VERSION 5.7 ;
  NOWIREEXTENSIONATPIN ON ;
  DIVIDERCHAR "/" ;
  BUSBITCHARS "[]" ;
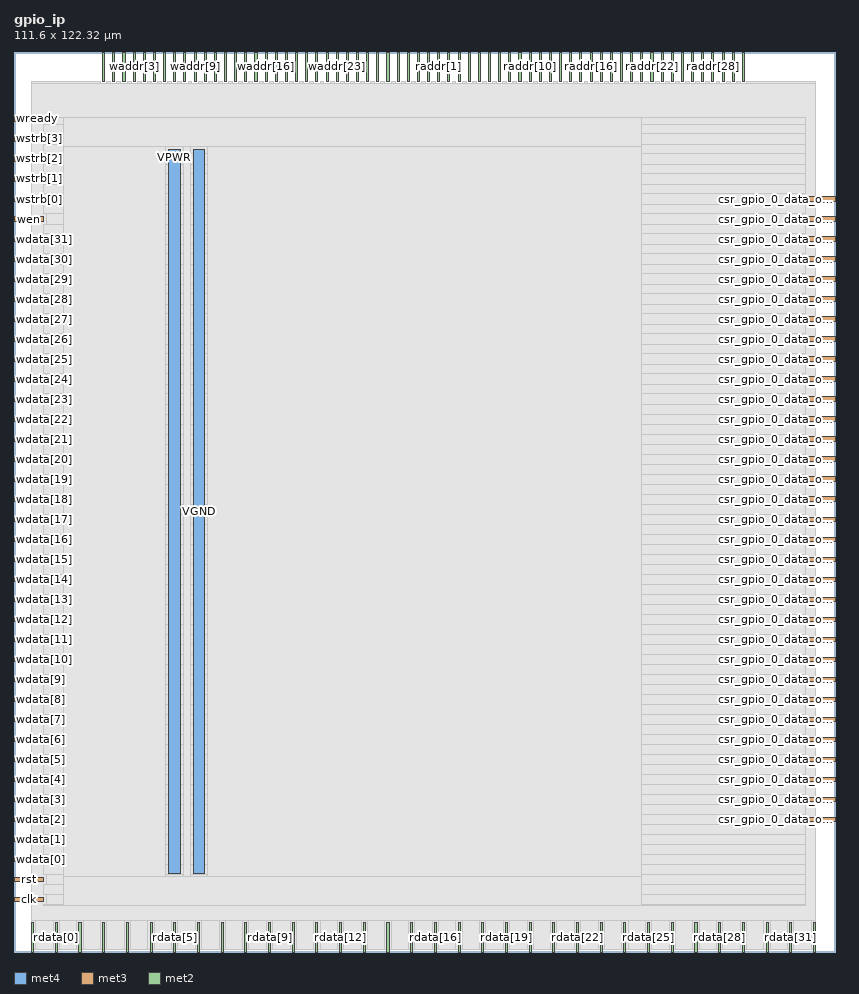
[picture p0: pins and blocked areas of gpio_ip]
MACRO gpio_ip
  CLASS BLOCK ;
  FOREIGN gpio_ip ;
  ORIGIN 0.000 0.000 ;
  SIZE 111.600 BY 122.320 ;
  PIN VGND
    DIRECTION INOUT ;
    USE GROUND ;
    PORT
      LAYER met4 ;
        RECT 24.340 10.640 25.940 109.040 ;
    END
  END VGND
  PIN VPWR
    DIRECTION INOUT ;
    USE POWER ;
    PORT
      LAYER met4 ;
        RECT 21.040 10.640 22.640 109.040 ;
    END
  END VPWR
  PIN clk
    DIRECTION INPUT ;
    USE SIGNAL ;
    ANTENNAGATEAREA 1.286700 ;
    ANTENNADIFFAREA 0.434700 ;
    PORT
      LAYER met3 ;
        RECT 0.000 6.840 4.000 7.440 ;
    END
  END clk
  PIN csr_gpio_0_data_out[0]
    DIRECTION OUTPUT ;
    USE SIGNAL ;
    ANTENNAGATEAREA 0.434700 ;
    ANTENNADIFFAREA 0.880200 ;
    PORT
      LAYER met3 ;
        RECT 107.600 17.720 111.600 18.320 ;
    END
  END csr_gpio_0_data_out[0]
  PIN csr_gpio_0_data_out[10]
    DIRECTION OUTPUT ;
    USE SIGNAL ;
    ANTENNAGATEAREA 0.434700 ;
    ANTENNADIFFAREA 0.880200 ;
    PORT
      LAYER met3 ;
        RECT 107.600 44.920 111.600 45.520 ;
    END
  END csr_gpio_0_data_out[10]
  PIN csr_gpio_0_data_out[11]
    DIRECTION OUTPUT ;
    USE SIGNAL ;
    ANTENNAGATEAREA 0.434700 ;
    ANTENNADIFFAREA 0.880200 ;
    PORT
      LAYER met3 ;
        RECT 107.600 47.640 111.600 48.240 ;
    END
  END csr_gpio_0_data_out[11]
  PIN csr_gpio_0_data_out[12]
    DIRECTION OUTPUT ;
    USE SIGNAL ;
    ANTENNAGATEAREA 0.434700 ;
    ANTENNADIFFAREA 0.880200 ;
    PORT
      LAYER met3 ;
        RECT 107.600 50.360 111.600 50.960 ;
    END
  END csr_gpio_0_data_out[12]
  PIN csr_gpio_0_data_out[13]
    DIRECTION OUTPUT ;
    USE SIGNAL ;
    ANTENNAGATEAREA 0.434700 ;
    ANTENNADIFFAREA 0.880200 ;
    PORT
      LAYER met3 ;
        RECT 107.600 53.080 111.600 53.680 ;
    END
  END csr_gpio_0_data_out[13]
  PIN csr_gpio_0_data_out[14]
    DIRECTION OUTPUT ;
    USE SIGNAL ;
    ANTENNAGATEAREA 0.434700 ;
    ANTENNADIFFAREA 0.880200 ;
    PORT
      LAYER met3 ;
        RECT 107.600 55.800 111.600 56.400 ;
    END
  END csr_gpio_0_data_out[14]
  PIN csr_gpio_0_data_out[15]
    DIRECTION OUTPUT ;
    USE SIGNAL ;
    ANTENNAGATEAREA 0.434700 ;
    ANTENNADIFFAREA 0.880200 ;
    PORT
      LAYER met3 ;
        RECT 107.600 58.520 111.600 59.120 ;
    END
  END csr_gpio_0_data_out[15]
  PIN csr_gpio_0_data_out[16]
    DIRECTION OUTPUT ;
    USE SIGNAL ;
    ANTENNAGATEAREA 0.434700 ;
    ANTENNADIFFAREA 0.880200 ;
    PORT
      LAYER met3 ;
        RECT 107.600 61.240 111.600 61.840 ;
    END
  END csr_gpio_0_data_out[16]
  PIN csr_gpio_0_data_out[17]
    DIRECTION OUTPUT ;
    USE SIGNAL ;
    ANTENNAGATEAREA 0.434700 ;
    ANTENNADIFFAREA 0.880200 ;
    PORT
      LAYER met3 ;
        RECT 107.600 63.960 111.600 64.560 ;
    END
  END csr_gpio_0_data_out[17]
  PIN csr_gpio_0_data_out[18]
    DIRECTION OUTPUT ;
    USE SIGNAL ;
    ANTENNAGATEAREA 0.434700 ;
    ANTENNADIFFAREA 0.880200 ;
    PORT
      LAYER met3 ;
        RECT 107.600 66.680 111.600 67.280 ;
    END
  END csr_gpio_0_data_out[18]
  PIN csr_gpio_0_data_out[19]
    DIRECTION OUTPUT ;
    USE SIGNAL ;
    ANTENNAGATEAREA 0.434700 ;
    ANTENNADIFFAREA 0.880200 ;
    PORT
      LAYER met3 ;
        RECT 107.600 69.400 111.600 70.000 ;
    END
  END csr_gpio_0_data_out[19]
  PIN csr_gpio_0_data_out[1]
    DIRECTION OUTPUT ;
    USE SIGNAL ;
    ANTENNAGATEAREA 0.434700 ;
    ANTENNADIFFAREA 0.880200 ;
    PORT
      LAYER met3 ;
        RECT 107.600 20.440 111.600 21.040 ;
    END
  END csr_gpio_0_data_out[1]
  PIN csr_gpio_0_data_out[20]
    DIRECTION OUTPUT ;
    USE SIGNAL ;
    ANTENNAGATEAREA 0.434700 ;
    ANTENNADIFFAREA 0.880200 ;
    PORT
      LAYER met3 ;
        RECT 107.600 72.120 111.600 72.720 ;
    END
  END csr_gpio_0_data_out[20]
  PIN csr_gpio_0_data_out[21]
    DIRECTION OUTPUT ;
    USE SIGNAL ;
    ANTENNAGATEAREA 0.434700 ;
    ANTENNADIFFAREA 0.880200 ;
    PORT
      LAYER met3 ;
        RECT 107.600 74.840 111.600 75.440 ;
    END
  END csr_gpio_0_data_out[21]
  PIN csr_gpio_0_data_out[22]
    DIRECTION OUTPUT ;
    USE SIGNAL ;
    ANTENNAGATEAREA 0.434700 ;
    ANTENNADIFFAREA 0.880200 ;
    PORT
      LAYER met3 ;
        RECT 107.600 77.560 111.600 78.160 ;
    END
  END csr_gpio_0_data_out[22]
  PIN csr_gpio_0_data_out[23]
    DIRECTION OUTPUT ;
    USE SIGNAL ;
    ANTENNAGATEAREA 0.434700 ;
    ANTENNADIFFAREA 0.880200 ;
    PORT
      LAYER met3 ;
        RECT 107.600 80.280 111.600 80.880 ;
    END
  END csr_gpio_0_data_out[23]
  PIN csr_gpio_0_data_out[24]
    DIRECTION OUTPUT ;
    USE SIGNAL ;
    ANTENNAGATEAREA 0.434700 ;
    ANTENNADIFFAREA 0.880200 ;
    PORT
      LAYER met3 ;
        RECT 107.600 83.000 111.600 83.600 ;
    END
  END csr_gpio_0_data_out[24]
  PIN csr_gpio_0_data_out[25]
    DIRECTION OUTPUT ;
    USE SIGNAL ;
    ANTENNAGATEAREA 0.434700 ;
    ANTENNADIFFAREA 0.880200 ;
    PORT
      LAYER met3 ;
        RECT 107.600 85.720 111.600 86.320 ;
    END
  END csr_gpio_0_data_out[25]
  PIN csr_gpio_0_data_out[26]
    DIRECTION OUTPUT ;
    USE SIGNAL ;
    ANTENNAGATEAREA 0.434700 ;
    ANTENNADIFFAREA 0.880200 ;
    PORT
      LAYER met3 ;
        RECT 107.600 88.440 111.600 89.040 ;
    END
  END csr_gpio_0_data_out[26]
  PIN csr_gpio_0_data_out[27]
    DIRECTION OUTPUT ;
    USE SIGNAL ;
    ANTENNAGATEAREA 0.434700 ;
    ANTENNADIFFAREA 0.880200 ;
    PORT
      LAYER met3 ;
        RECT 107.600 91.160 111.600 91.760 ;
    END
  END csr_gpio_0_data_out[27]
  PIN csr_gpio_0_data_out[28]
    DIRECTION OUTPUT ;
    USE SIGNAL ;
    ANTENNAGATEAREA 0.434700 ;
    ANTENNADIFFAREA 0.880200 ;
    PORT
      LAYER met3 ;
        RECT 107.600 93.880 111.600 94.480 ;
    END
  END csr_gpio_0_data_out[28]
  PIN csr_gpio_0_data_out[29]
    DIRECTION OUTPUT ;
    USE SIGNAL ;
    ANTENNAGATEAREA 0.434700 ;
    ANTENNADIFFAREA 0.880200 ;
    PORT
      LAYER met3 ;
        RECT 107.600 96.600 111.600 97.200 ;
    END
  END csr_gpio_0_data_out[29]
  PIN csr_gpio_0_data_out[2]
    DIRECTION OUTPUT ;
    USE SIGNAL ;
    ANTENNAGATEAREA 0.434700 ;
    ANTENNADIFFAREA 0.880200 ;
    PORT
      LAYER met3 ;
        RECT 107.600 23.160 111.600 23.760 ;
    END
  END csr_gpio_0_data_out[2]
  PIN csr_gpio_0_data_out[30]
    DIRECTION OUTPUT ;
    USE SIGNAL ;
    ANTENNAGATEAREA 0.434700 ;
    ANTENNADIFFAREA 0.880200 ;
    PORT
      LAYER met3 ;
        RECT 107.600 99.320 111.600 99.920 ;
    END
  END csr_gpio_0_data_out[30]
  PIN csr_gpio_0_data_out[31]
    DIRECTION OUTPUT ;
    USE SIGNAL ;
    ANTENNAGATEAREA 0.434700 ;
    ANTENNADIFFAREA 0.880200 ;
    PORT
      LAYER met3 ;
        RECT 107.600 102.040 111.600 102.640 ;
    END
  END csr_gpio_0_data_out[31]
  PIN csr_gpio_0_data_out[3]
    DIRECTION OUTPUT ;
    USE SIGNAL ;
    ANTENNAGATEAREA 0.434700 ;
    ANTENNADIFFAREA 0.880200 ;
    PORT
      LAYER met3 ;
        RECT 107.600 25.880 111.600 26.480 ;
    END
  END csr_gpio_0_data_out[3]
  PIN csr_gpio_0_data_out[4]
    DIRECTION OUTPUT ;
    USE SIGNAL ;
    ANTENNAGATEAREA 0.434700 ;
    ANTENNADIFFAREA 0.880200 ;
    PORT
      LAYER met3 ;
        RECT 107.600 28.600 111.600 29.200 ;
    END
  END csr_gpio_0_data_out[4]
  PIN csr_gpio_0_data_out[5]
    DIRECTION OUTPUT ;
    USE SIGNAL ;
    ANTENNAGATEAREA 0.434700 ;
    ANTENNADIFFAREA 0.880200 ;
    PORT
      LAYER met3 ;
        RECT 107.600 31.320 111.600 31.920 ;
    END
  END csr_gpio_0_data_out[5]
  PIN csr_gpio_0_data_out[6]
    DIRECTION OUTPUT ;
    USE SIGNAL ;
    ANTENNAGATEAREA 0.434700 ;
    ANTENNADIFFAREA 0.880200 ;
    PORT
      LAYER met3 ;
        RECT 107.600 34.040 111.600 34.640 ;
    END
  END csr_gpio_0_data_out[6]
  PIN csr_gpio_0_data_out[7]
    DIRECTION OUTPUT ;
    USE SIGNAL ;
    ANTENNAGATEAREA 0.434700 ;
    ANTENNADIFFAREA 0.880200 ;
    PORT
      LAYER met3 ;
        RECT 107.600 36.760 111.600 37.360 ;
    END
  END csr_gpio_0_data_out[7]
  PIN csr_gpio_0_data_out[8]
    DIRECTION OUTPUT ;
    USE SIGNAL ;
    ANTENNAGATEAREA 0.434700 ;
    ANTENNADIFFAREA 0.880200 ;
    PORT
      LAYER met3 ;
        RECT 107.600 39.480 111.600 40.080 ;
    END
  END csr_gpio_0_data_out[8]
  PIN csr_gpio_0_data_out[9]
    DIRECTION OUTPUT ;
    USE SIGNAL ;
    ANTENNAGATEAREA 0.434700 ;
    ANTENNADIFFAREA 0.880200 ;
    PORT
      LAYER met3 ;
        RECT 107.600 42.200 111.600 42.800 ;
    END
  END csr_gpio_0_data_out[9]
  PIN raddr[0]
    DIRECTION INPUT ;
    USE SIGNAL ;
    ANTENNAGATEAREA 0.631200 ;
    ANTENNADIFFAREA 0.434700 ;
    PORT
      LAYER met2 ;
        RECT 56.210 118.320 56.490 122.320 ;
    END
  END raddr[0]
  PIN raddr[10]
    DIRECTION INPUT ;
    USE SIGNAL ;
    ANTENNAGATEAREA 0.631200 ;
    ANTENNADIFFAREA 0.434700 ;
    PORT
      LAYER met2 ;
        RECT 70.010 118.320 70.290 122.320 ;
    END
  END raddr[10]
  PIN raddr[11]
    DIRECTION INPUT ;
    USE SIGNAL ;
    ANTENNAGATEAREA 0.631200 ;
    ANTENNADIFFAREA 0.434700 ;
    PORT
      LAYER met2 ;
        RECT 71.390 118.320 71.670 122.320 ;
    END
  END raddr[11]
  PIN raddr[12]
    DIRECTION INPUT ;
    USE SIGNAL ;
    ANTENNAGATEAREA 0.631200 ;
    ANTENNADIFFAREA 0.434700 ;
    PORT
      LAYER met2 ;
        RECT 72.770 118.320 73.050 122.320 ;
    END
  END raddr[12]
  PIN raddr[13]
    DIRECTION INPUT ;
    USE SIGNAL ;
    ANTENNAGATEAREA 0.631200 ;
    ANTENNADIFFAREA 0.434700 ;
    PORT
      LAYER met2 ;
        RECT 74.150 118.320 74.430 122.320 ;
    END
  END raddr[13]
  PIN raddr[14]
    DIRECTION INPUT ;
    USE SIGNAL ;
    ANTENNAGATEAREA 0.631200 ;
    ANTENNADIFFAREA 0.434700 ;
    PORT
      LAYER met2 ;
        RECT 75.530 118.320 75.810 122.320 ;
    END
  END raddr[14]
  PIN raddr[15]
    DIRECTION INPUT ;
    USE SIGNAL ;
    ANTENNAGATEAREA 0.631200 ;
    ANTENNADIFFAREA 0.434700 ;
    PORT
      LAYER met2 ;
        RECT 76.910 118.320 77.190 122.320 ;
    END
  END raddr[15]
  PIN raddr[16]
    DIRECTION INPUT ;
    USE SIGNAL ;
    ANTENNAGATEAREA 0.631200 ;
    ANTENNADIFFAREA 0.434700 ;
    PORT
      LAYER met2 ;
        RECT 78.290 118.320 78.570 122.320 ;
    END
  END raddr[16]
  PIN raddr[17]
    DIRECTION INPUT ;
    USE SIGNAL ;
    ANTENNAGATEAREA 0.631200 ;
    ANTENNADIFFAREA 0.434700 ;
    PORT
      LAYER met2 ;
        RECT 79.670 118.320 79.950 122.320 ;
    END
  END raddr[17]
  PIN raddr[18]
    DIRECTION INPUT ;
    USE SIGNAL ;
    ANTENNAGATEAREA 0.631200 ;
    ANTENNADIFFAREA 0.434700 ;
    PORT
      LAYER met2 ;
        RECT 81.050 118.320 81.330 122.320 ;
    END
  END raddr[18]
  PIN raddr[19]
    DIRECTION INPUT ;
    USE SIGNAL ;
    ANTENNAGATEAREA 0.631200 ;
    ANTENNADIFFAREA 0.434700 ;
    PORT
      LAYER met2 ;
        RECT 82.430 118.320 82.710 122.320 ;
    END
  END raddr[19]
  PIN raddr[1]
    DIRECTION INPUT ;
    USE SIGNAL ;
    ANTENNAGATEAREA 0.631200 ;
    ANTENNADIFFAREA 0.434700 ;
    PORT
      LAYER met2 ;
        RECT 57.590 118.320 57.870 122.320 ;
    END
  END raddr[1]
  PIN raddr[20]
    DIRECTION INPUT ;
    USE SIGNAL ;
    ANTENNAGATEAREA 0.631200 ;
    ANTENNADIFFAREA 0.434700 ;
    PORT
      LAYER met2 ;
        RECT 83.810 118.320 84.090 122.320 ;
    END
  END raddr[20]
  PIN raddr[21]
    DIRECTION INPUT ;
    USE SIGNAL ;
    ANTENNAGATEAREA 0.631200 ;
    ANTENNADIFFAREA 0.434700 ;
    PORT
      LAYER met2 ;
        RECT 85.190 118.320 85.470 122.320 ;
    END
  END raddr[21]
  PIN raddr[22]
    DIRECTION INPUT ;
    USE SIGNAL ;
    ANTENNAGATEAREA 0.631200 ;
    ANTENNADIFFAREA 0.434700 ;
    PORT
      LAYER met2 ;
        RECT 86.570 118.320 86.850 122.320 ;
    END
  END raddr[22]
  PIN raddr[23]
    DIRECTION INPUT ;
    USE SIGNAL ;
    ANTENNAGATEAREA 0.631200 ;
    ANTENNADIFFAREA 0.434700 ;
    PORT
      LAYER met2 ;
        RECT 87.950 118.320 88.230 122.320 ;
    END
  END raddr[23]
  PIN raddr[24]
    DIRECTION INPUT ;
    USE SIGNAL ;
    ANTENNAGATEAREA 0.631200 ;
    ANTENNADIFFAREA 0.434700 ;
    PORT
      LAYER met2 ;
        RECT 89.330 118.320 89.610 122.320 ;
    END
  END raddr[24]
  PIN raddr[25]
    DIRECTION INPUT ;
    USE SIGNAL ;
    ANTENNAGATEAREA 0.560700 ;
    ANTENNADIFFAREA 0.434700 ;
    PORT
      LAYER met2 ;
        RECT 90.710 118.320 90.990 122.320 ;
    END
  END raddr[25]
  PIN raddr[26]
    DIRECTION INPUT ;
    USE SIGNAL ;
    ANTENNAGATEAREA 0.631200 ;
    ANTENNADIFFAREA 0.434700 ;
    PORT
      LAYER met2 ;
        RECT 92.090 118.320 92.370 122.320 ;
    END
  END raddr[26]
  PIN raddr[27]
    DIRECTION INPUT ;
    USE SIGNAL ;
    ANTENNAGATEAREA 0.631200 ;
    ANTENNADIFFAREA 0.434700 ;
    PORT
      LAYER met2 ;
        RECT 93.470 118.320 93.750 122.320 ;
    END
  END raddr[27]
  PIN raddr[28]
    DIRECTION INPUT ;
    USE SIGNAL ;
    ANTENNAGATEAREA 0.631200 ;
    ANTENNADIFFAREA 0.434700 ;
    PORT
      LAYER met2 ;
        RECT 94.850 118.320 95.130 122.320 ;
    END
  END raddr[28]
  PIN raddr[29]
    DIRECTION INPUT ;
    USE SIGNAL ;
    ANTENNAGATEAREA 0.631200 ;
    ANTENNADIFFAREA 0.434700 ;
    PORT
      LAYER met2 ;
        RECT 96.230 118.320 96.510 122.320 ;
    END
  END raddr[29]
  PIN raddr[2]
    DIRECTION INPUT ;
    USE SIGNAL ;
    ANTENNAGATEAREA 0.631200 ;
    ANTENNADIFFAREA 0.434700 ;
    PORT
      LAYER met2 ;
        RECT 58.970 118.320 59.250 122.320 ;
    END
  END raddr[2]
  PIN raddr[30]
    DIRECTION INPUT ;
    USE SIGNAL ;
    ANTENNAGATEAREA 0.631200 ;
    ANTENNADIFFAREA 0.434700 ;
    PORT
      LAYER met2 ;
        RECT 97.610 118.320 97.890 122.320 ;
    END
  END raddr[30]
  PIN raddr[31]
    DIRECTION INPUT ;
    USE SIGNAL ;
    ANTENNAGATEAREA 0.631200 ;
    ANTENNADIFFAREA 0.434700 ;
    PORT
      LAYER met2 ;
        RECT 98.990 118.320 99.270 122.320 ;
    END
  END raddr[31]
  PIN raddr[3]
    DIRECTION INPUT ;
    USE SIGNAL ;
    ANTENNAGATEAREA 0.631200 ;
    ANTENNADIFFAREA 0.434700 ;
    PORT
      LAYER met2 ;
        RECT 60.350 118.320 60.630 122.320 ;
    END
  END raddr[3]
  PIN raddr[4]
    DIRECTION INPUT ;
    USE SIGNAL ;
    ANTENNAGATEAREA 0.631200 ;
    ANTENNADIFFAREA 0.434700 ;
    PORT
      LAYER met2 ;
        RECT 61.730 118.320 62.010 122.320 ;
    END
  END raddr[4]
  PIN raddr[5]
    DIRECTION INPUT ;
    USE SIGNAL ;
    ANTENNAGATEAREA 0.631200 ;
    ANTENNADIFFAREA 0.434700 ;
    PORT
      LAYER met2 ;
        RECT 63.110 118.320 63.390 122.320 ;
    END
  END raddr[5]
  PIN raddr[6]
    DIRECTION INPUT ;
    USE SIGNAL ;
    ANTENNAGATEAREA 0.631200 ;
    ANTENNADIFFAREA 0.434700 ;
    PORT
      LAYER met2 ;
        RECT 64.490 118.320 64.770 122.320 ;
    END
  END raddr[6]
  PIN raddr[7]
    DIRECTION INPUT ;
    USE SIGNAL ;
    ANTENNAGATEAREA 0.631200 ;
    ANTENNADIFFAREA 0.434700 ;
    PORT
      LAYER met2 ;
        RECT 65.870 118.320 66.150 122.320 ;
    END
  END raddr[7]
  PIN raddr[8]
    DIRECTION INPUT ;
    USE SIGNAL ;
    ANTENNAGATEAREA 0.631200 ;
    ANTENNADIFFAREA 0.434700 ;
    PORT
      LAYER met2 ;
        RECT 67.250 118.320 67.530 122.320 ;
    END
  END raddr[8]
  PIN raddr[9]
    DIRECTION INPUT ;
    USE SIGNAL ;
    ANTENNAGATEAREA 0.560700 ;
    ANTENNADIFFAREA 0.434700 ;
    PORT
      LAYER met2 ;
        RECT 68.630 118.320 68.910 122.320 ;
    END
  END raddr[9]
  PIN rdata[0]
    DIRECTION OUTPUT ;
    USE SIGNAL ;
    ANTENNAGATEAREA 0.434700 ;
    ANTENNADIFFAREA 0.880200 ;
    PORT
      LAYER met2 ;
        RECT 5.610 0.000 5.890 4.000 ;
    END
  END rdata[0]
  PIN rdata[10]
    DIRECTION OUTPUT ;
    USE SIGNAL ;
    ANTENNAGATEAREA 0.434700 ;
    ANTENNADIFFAREA 0.880200 ;
    PORT
      LAYER met2 ;
        RECT 37.810 0.000 38.090 4.000 ;
    END
  END rdata[10]
  PIN rdata[11]
    DIRECTION OUTPUT ;
    USE SIGNAL ;
    ANTENNAGATEAREA 0.434700 ;
    ANTENNADIFFAREA 0.880200 ;
    PORT
      LAYER met2 ;
        RECT 41.030 0.000 41.310 4.000 ;
    END
  END rdata[11]
  PIN rdata[12]
    DIRECTION OUTPUT ;
    USE SIGNAL ;
    ANTENNAGATEAREA 0.434700 ;
    ANTENNADIFFAREA 0.880200 ;
    PORT
      LAYER met2 ;
        RECT 44.250 0.000 44.530 4.000 ;
    END
  END rdata[12]
  PIN rdata[13]
    DIRECTION OUTPUT ;
    USE SIGNAL ;
    ANTENNAGATEAREA 0.434700 ;
    ANTENNADIFFAREA 0.880200 ;
    PORT
      LAYER met2 ;
        RECT 47.470 0.000 47.750 4.000 ;
    END
  END rdata[13]
  PIN rdata[14]
    DIRECTION OUTPUT ;
    USE SIGNAL ;
    ANTENNAGATEAREA 0.434700 ;
    ANTENNADIFFAREA 0.880200 ;
    PORT
      LAYER met2 ;
        RECT 50.690 0.000 50.970 4.000 ;
    END
  END rdata[14]
  PIN rdata[15]
    DIRECTION OUTPUT ;
    USE SIGNAL ;
    ANTENNAGATEAREA 0.434700 ;
    ANTENNADIFFAREA 0.880200 ;
    PORT
      LAYER met2 ;
        RECT 53.910 0.000 54.190 4.000 ;
    END
  END rdata[15]
  PIN rdata[16]
    DIRECTION OUTPUT ;
    USE SIGNAL ;
    ANTENNAGATEAREA 0.434700 ;
    ANTENNADIFFAREA 0.880200 ;
    PORT
      LAYER met2 ;
        RECT 57.130 0.000 57.410 4.000 ;
    END
  END rdata[16]
  PIN rdata[17]
    DIRECTION OUTPUT ;
    USE SIGNAL ;
    ANTENNAGATEAREA 0.434700 ;
    ANTENNADIFFAREA 0.880200 ;
    PORT
      LAYER met2 ;
        RECT 60.350 0.000 60.630 4.000 ;
    END
  END rdata[17]
  PIN rdata[18]
    DIRECTION OUTPUT ;
    USE SIGNAL ;
    ANTENNAGATEAREA 0.434700 ;
    ANTENNADIFFAREA 0.880200 ;
    PORT
      LAYER met2 ;
        RECT 63.570 0.000 63.850 4.000 ;
    END
  END rdata[18]
  PIN rdata[19]
    DIRECTION OUTPUT ;
    USE SIGNAL ;
    ANTENNAGATEAREA 0.434700 ;
    ANTENNADIFFAREA 0.880200 ;
    PORT
      LAYER met2 ;
        RECT 66.790 0.000 67.070 4.000 ;
    END
  END rdata[19]
  PIN rdata[1]
    DIRECTION OUTPUT ;
    USE SIGNAL ;
    ANTENNAGATEAREA 0.434700 ;
    ANTENNADIFFAREA 0.880200 ;
    PORT
      LAYER met2 ;
        RECT 8.830 0.000 9.110 4.000 ;
    END
  END rdata[1]
  PIN rdata[20]
    DIRECTION OUTPUT ;
    USE SIGNAL ;
    ANTENNAGATEAREA 0.434700 ;
    ANTENNADIFFAREA 0.880200 ;
    PORT
      LAYER met2 ;
        RECT 70.010 0.000 70.290 4.000 ;
    END
  END rdata[20]
  PIN rdata[21]
    DIRECTION OUTPUT ;
    USE SIGNAL ;
    ANTENNAGATEAREA 0.434700 ;
    ANTENNADIFFAREA 0.880200 ;
    PORT
      LAYER met2 ;
        RECT 73.230 0.000 73.510 4.000 ;
    END
  END rdata[21]
  PIN rdata[22]
    DIRECTION OUTPUT ;
    USE SIGNAL ;
    ANTENNAGATEAREA 0.434700 ;
    ANTENNADIFFAREA 0.880200 ;
    PORT
      LAYER met2 ;
        RECT 76.450 0.000 76.730 4.000 ;
    END
  END rdata[22]
  PIN rdata[23]
    DIRECTION OUTPUT ;
    USE SIGNAL ;
    ANTENNAGATEAREA 0.434700 ;
    ANTENNADIFFAREA 0.880200 ;
    PORT
      LAYER met2 ;
        RECT 79.670 0.000 79.950 4.000 ;
    END
  END rdata[23]
  PIN rdata[24]
    DIRECTION OUTPUT ;
    USE SIGNAL ;
    ANTENNAGATEAREA 0.434700 ;
    ANTENNADIFFAREA 0.880200 ;
    PORT
      LAYER met2 ;
        RECT 82.890 0.000 83.170 4.000 ;
    END
  END rdata[24]
  PIN rdata[25]
    DIRECTION OUTPUT ;
    USE SIGNAL ;
    ANTENNAGATEAREA 0.434700 ;
    ANTENNADIFFAREA 0.880200 ;
    PORT
      LAYER met2 ;
        RECT 86.110 0.000 86.390 4.000 ;
    END
  END rdata[25]
  PIN rdata[26]
    DIRECTION OUTPUT ;
    USE SIGNAL ;
    ANTENNAGATEAREA 0.434700 ;
    ANTENNADIFFAREA 0.880200 ;
    PORT
      LAYER met2 ;
        RECT 89.330 0.000 89.610 4.000 ;
    END
  END rdata[26]
  PIN rdata[27]
    DIRECTION OUTPUT ;
    USE SIGNAL ;
    ANTENNAGATEAREA 0.434700 ;
    ANTENNADIFFAREA 0.880200 ;
    PORT
      LAYER met2 ;
        RECT 92.550 0.000 92.830 4.000 ;
    END
  END rdata[27]
  PIN rdata[28]
    DIRECTION OUTPUT ;
    USE SIGNAL ;
    ANTENNAGATEAREA 0.434700 ;
    ANTENNADIFFAREA 0.880200 ;
    PORT
      LAYER met2 ;
        RECT 95.770 0.000 96.050 4.000 ;
    END
  END rdata[28]
  PIN rdata[29]
    DIRECTION OUTPUT ;
    USE SIGNAL ;
    ANTENNAGATEAREA 0.434700 ;
    ANTENNADIFFAREA 0.880200 ;
    PORT
      LAYER met2 ;
        RECT 98.990 0.000 99.270 4.000 ;
    END
  END rdata[29]
  PIN rdata[2]
    DIRECTION OUTPUT ;
    USE SIGNAL ;
    ANTENNAGATEAREA 0.434700 ;
    ANTENNADIFFAREA 0.880200 ;
    PORT
      LAYER met2 ;
        RECT 12.050 0.000 12.330 4.000 ;
    END
  END rdata[2]
  PIN rdata[30]
    DIRECTION OUTPUT ;
    USE SIGNAL ;
    ANTENNAGATEAREA 0.434700 ;
    ANTENNADIFFAREA 0.880200 ;
    PORT
      LAYER met2 ;
        RECT 102.210 0.000 102.490 4.000 ;
    END
  END rdata[30]
  PIN rdata[31]
    DIRECTION OUTPUT ;
    USE SIGNAL ;
    ANTENNAGATEAREA 0.434700 ;
    ANTENNADIFFAREA 0.880200 ;
    PORT
      LAYER met2 ;
        RECT 105.430 0.000 105.710 4.000 ;
    END
  END rdata[31]
  PIN rdata[3]
    DIRECTION OUTPUT ;
    USE SIGNAL ;
    ANTENNAGATEAREA 0.434700 ;
    ANTENNADIFFAREA 0.880200 ;
    PORT
      LAYER met2 ;
        RECT 15.270 0.000 15.550 4.000 ;
    END
  END rdata[3]
  PIN rdata[4]
    DIRECTION OUTPUT ;
    USE SIGNAL ;
    ANTENNAGATEAREA 0.434700 ;
    ANTENNADIFFAREA 0.880200 ;
    PORT
      LAYER met2 ;
        RECT 18.490 0.000 18.770 4.000 ;
    END
  END rdata[4]
  PIN rdata[5]
    DIRECTION OUTPUT ;
    USE SIGNAL ;
    ANTENNAGATEAREA 0.434700 ;
    ANTENNADIFFAREA 0.880200 ;
    PORT
      LAYER met2 ;
        RECT 21.710 0.000 21.990 4.000 ;
    END
  END rdata[5]
  PIN rdata[6]
    DIRECTION OUTPUT ;
    USE SIGNAL ;
    ANTENNAGATEAREA 0.434700 ;
    ANTENNADIFFAREA 0.880200 ;
    PORT
      LAYER met2 ;
        RECT 24.930 0.000 25.210 4.000 ;
    END
  END rdata[6]
  PIN rdata[7]
    DIRECTION OUTPUT ;
    USE SIGNAL ;
    ANTENNAGATEAREA 0.434700 ;
    ANTENNADIFFAREA 0.880200 ;
    PORT
      LAYER met2 ;
        RECT 28.150 0.000 28.430 4.000 ;
    END
  END rdata[7]
  PIN rdata[8]
    DIRECTION OUTPUT ;
    USE SIGNAL ;
    ANTENNAGATEAREA 0.434700 ;
    ANTENNADIFFAREA 0.880200 ;
    PORT
      LAYER met2 ;
        RECT 31.370 0.000 31.650 4.000 ;
    END
  END rdata[8]
  PIN rdata[9]
    DIRECTION OUTPUT ;
    USE SIGNAL ;
    ANTENNAGATEAREA 0.434700 ;
    ANTENNADIFFAREA 0.880200 ;
    PORT
      LAYER met2 ;
        RECT 34.590 0.000 34.870 4.000 ;
    END
  END rdata[9]
  PIN ren
    DIRECTION INPUT ;
    USE SIGNAL ;
    ANTENNAGATEAREA 0.560700 ;
    ANTENNADIFFAREA 0.434700 ;
    PORT
      LAYER met2 ;
        RECT 2.390 0.000 2.670 4.000 ;
    END
  END ren
  PIN rst
    DIRECTION INPUT ;
    USE SIGNAL ;
    ANTENNAGATEAREA 0.560700 ;
    ANTENNADIFFAREA 0.434700 ;
    PORT
      LAYER met3 ;
        RECT 0.000 9.560 4.000 10.160 ;
    END
  END rst
  PIN rvalid
    DIRECTION OUTPUT ;
    USE SIGNAL ;
    ANTENNAGATEAREA 0.434700 ;
    ANTENNADIFFAREA 0.880200 ;
    PORT
      LAYER met2 ;
        RECT 108.650 0.000 108.930 4.000 ;
    END
  END rvalid
  PIN waddr[0]
    DIRECTION INPUT ;
    USE SIGNAL ;
    ANTENNAGATEAREA 0.631200 ;
    ANTENNADIFFAREA 0.434700 ;
    PORT
      LAYER met2 ;
        RECT 12.050 118.320 12.330 122.320 ;
    END
  END waddr[0]
  PIN waddr[10]
    DIRECTION INPUT ;
    USE SIGNAL ;
    ANTENNAGATEAREA 0.631200 ;
    ANTENNADIFFAREA 0.434700 ;
    PORT
      LAYER met2 ;
        RECT 25.850 118.320 26.130 122.320 ;
    END
  END waddr[10]
  PIN waddr[11]
    DIRECTION INPUT ;
    USE SIGNAL ;
    ANTENNAGATEAREA 0.631200 ;
    ANTENNADIFFAREA 0.434700 ;
    PORT
      LAYER met2 ;
        RECT 27.230 118.320 27.510 122.320 ;
    END
  END waddr[11]
  PIN waddr[12]
    DIRECTION INPUT ;
    USE SIGNAL ;
    ANTENNAGATEAREA 0.631200 ;
    ANTENNADIFFAREA 0.434700 ;
    PORT
      LAYER met2 ;
        RECT 28.610 118.320 28.890 122.320 ;
    END
  END waddr[12]
  PIN waddr[13]
    DIRECTION INPUT ;
    USE SIGNAL ;
    ANTENNAGATEAREA 0.631200 ;
    ANTENNADIFFAREA 0.434700 ;
    PORT
      LAYER met2 ;
        RECT 29.990 118.320 30.270 122.320 ;
    END
  END waddr[13]
  PIN waddr[14]
    DIRECTION INPUT ;
    USE SIGNAL ;
    ANTENNAGATEAREA 0.631200 ;
    ANTENNADIFFAREA 0.434700 ;
    PORT
      LAYER met2 ;
        RECT 31.370 118.320 31.650 122.320 ;
    END
  END waddr[14]
  PIN waddr[15]
    DIRECTION INPUT ;
    USE SIGNAL ;
    ANTENNAGATEAREA 0.631200 ;
    ANTENNADIFFAREA 0.434700 ;
    PORT
      LAYER met2 ;
        RECT 32.750 118.320 33.030 122.320 ;
    END
  END waddr[15]
  PIN waddr[16]
    DIRECTION INPUT ;
    USE SIGNAL ;
    ANTENNAGATEAREA 0.631200 ;
    ANTENNADIFFAREA 0.434700 ;
    PORT
      LAYER met2 ;
        RECT 34.130 118.320 34.410 122.320 ;
    END
  END waddr[16]
  PIN waddr[17]
    DIRECTION INPUT ;
    USE SIGNAL ;
    ANTENNAGATEAREA 0.631200 ;
    ANTENNADIFFAREA 0.434700 ;
    PORT
      LAYER met2 ;
        RECT 35.510 118.320 35.790 122.320 ;
    END
  END waddr[17]
  PIN waddr[18]
    DIRECTION INPUT ;
    USE SIGNAL ;
    ANTENNAGATEAREA 0.631200 ;
    ANTENNADIFFAREA 0.434700 ;
    PORT
      LAYER met2 ;
        RECT 36.890 118.320 37.170 122.320 ;
    END
  END waddr[18]
  PIN waddr[19]
    DIRECTION INPUT ;
    USE SIGNAL ;
    ANTENNAGATEAREA 0.631200 ;
    ANTENNADIFFAREA 0.434700 ;
    PORT
      LAYER met2 ;
        RECT 38.270 118.320 38.550 122.320 ;
    END
  END waddr[19]
  PIN waddr[1]
    DIRECTION INPUT ;
    USE SIGNAL ;
    ANTENNAGATEAREA 0.631200 ;
    ANTENNADIFFAREA 0.434700 ;
    PORT
      LAYER met2 ;
        RECT 13.430 118.320 13.710 122.320 ;
    END
  END waddr[1]
  PIN waddr[20]
    DIRECTION INPUT ;
    USE SIGNAL ;
    ANTENNAGATEAREA 0.631200 ;
    ANTENNADIFFAREA 0.434700 ;
    PORT
      LAYER met2 ;
        RECT 39.650 118.320 39.930 122.320 ;
    END
  END waddr[20]
  PIN waddr[21]
    DIRECTION INPUT ;
    USE SIGNAL ;
    ANTENNAGATEAREA 0.631200 ;
    ANTENNADIFFAREA 0.434700 ;
    PORT
      LAYER met2 ;
        RECT 41.030 118.320 41.310 122.320 ;
    END
  END waddr[21]
  PIN waddr[22]
    DIRECTION INPUT ;
    USE SIGNAL ;
    ANTENNAGATEAREA 0.631200 ;
    ANTENNADIFFAREA 0.434700 ;
    PORT
      LAYER met2 ;
        RECT 42.410 118.320 42.690 122.320 ;
    END
  END waddr[22]
  PIN waddr[23]
    DIRECTION INPUT ;
    USE SIGNAL ;
    ANTENNAGATEAREA 0.631200 ;
    ANTENNADIFFAREA 0.434700 ;
    PORT
      LAYER met2 ;
        RECT 43.790 118.320 44.070 122.320 ;
    END
  END waddr[23]
  PIN waddr[24]
    DIRECTION INPUT ;
    USE SIGNAL ;
    ANTENNAGATEAREA 0.631200 ;
    ANTENNADIFFAREA 0.434700 ;
    PORT
      LAYER met2 ;
        RECT 45.170 118.320 45.450 122.320 ;
    END
  END waddr[24]
  PIN waddr[25]
    DIRECTION INPUT ;
    USE SIGNAL ;
    ANTENNAGATEAREA 0.631200 ;
    ANTENNADIFFAREA 0.434700 ;
    PORT
      LAYER met2 ;
        RECT 46.550 118.320 46.830 122.320 ;
    END
  END waddr[25]
  PIN waddr[26]
    DIRECTION INPUT ;
    USE SIGNAL ;
    ANTENNAGATEAREA 0.631200 ;
    ANTENNADIFFAREA 0.434700 ;
    PORT
      LAYER met2 ;
        RECT 47.930 118.320 48.210 122.320 ;
    END
  END waddr[26]
  PIN waddr[27]
    DIRECTION INPUT ;
    USE SIGNAL ;
    ANTENNAGATEAREA 0.631200 ;
    ANTENNADIFFAREA 0.434700 ;
    PORT
      LAYER met2 ;
        RECT 49.310 118.320 49.590 122.320 ;
    END
  END waddr[27]
  PIN waddr[28]
    DIRECTION INPUT ;
    USE SIGNAL ;
    ANTENNAGATEAREA 0.631200 ;
    ANTENNADIFFAREA 0.434700 ;
    PORT
      LAYER met2 ;
        RECT 50.690 118.320 50.970 122.320 ;
    END
  END waddr[28]
  PIN waddr[29]
    DIRECTION INPUT ;
    USE SIGNAL ;
    ANTENNAGATEAREA 0.631200 ;
    ANTENNADIFFAREA 0.434700 ;
    PORT
      LAYER met2 ;
        RECT 52.070 118.320 52.350 122.320 ;
    END
  END waddr[29]
  PIN waddr[2]
    DIRECTION INPUT ;
    USE SIGNAL ;
    ANTENNAGATEAREA 0.631200 ;
    ANTENNADIFFAREA 0.434700 ;
    PORT
      LAYER met2 ;
        RECT 14.810 118.320 15.090 122.320 ;
    END
  END waddr[2]
  PIN waddr[30]
    DIRECTION INPUT ;
    USE SIGNAL ;
    ANTENNAGATEAREA 0.631200 ;
    ANTENNADIFFAREA 0.434700 ;
    PORT
      LAYER met2 ;
        RECT 53.450 118.320 53.730 122.320 ;
    END
  END waddr[30]
  PIN waddr[31]
    DIRECTION INPUT ;
    USE SIGNAL ;
    ANTENNAGATEAREA 0.631200 ;
    ANTENNADIFFAREA 0.434700 ;
    PORT
      LAYER met2 ;
        RECT 54.830 118.320 55.110 122.320 ;
    END
  END waddr[31]
  PIN waddr[3]
    DIRECTION INPUT ;
    USE SIGNAL ;
    ANTENNAGATEAREA 0.560700 ;
    ANTENNADIFFAREA 0.434700 ;
    PORT
      LAYER met2 ;
        RECT 16.190 118.320 16.470 122.320 ;
    END
  END waddr[3]
  PIN waddr[4]
    DIRECTION INPUT ;
    USE SIGNAL ;
    ANTENNAGATEAREA 0.631200 ;
    ANTENNADIFFAREA 0.434700 ;
    PORT
      LAYER met2 ;
        RECT 17.570 118.320 17.850 122.320 ;
    END
  END waddr[4]
  PIN waddr[5]
    DIRECTION INPUT ;
    USE SIGNAL ;
    ANTENNAGATEAREA 0.631200 ;
    ANTENNADIFFAREA 0.434700 ;
    PORT
      LAYER met2 ;
        RECT 18.950 118.320 19.230 122.320 ;
    END
  END waddr[5]
  PIN waddr[6]
    DIRECTION INPUT ;
    USE SIGNAL ;
    ANTENNAGATEAREA 0.631200 ;
    ANTENNADIFFAREA 0.434700 ;
    PORT
      LAYER met2 ;
        RECT 20.330 118.320 20.610 122.320 ;
    END
  END waddr[6]
  PIN waddr[7]
    DIRECTION INPUT ;
    USE SIGNAL ;
    ANTENNAGATEAREA 0.631200 ;
    ANTENNADIFFAREA 0.434700 ;
    PORT
      LAYER met2 ;
        RECT 21.710 118.320 21.990 122.320 ;
    END
  END waddr[7]
  PIN waddr[8]
    DIRECTION INPUT ;
    USE SIGNAL ;
    ANTENNAGATEAREA 0.631200 ;
    ANTENNADIFFAREA 0.434700 ;
    PORT
      LAYER met2 ;
        RECT 23.090 118.320 23.370 122.320 ;
    END
  END waddr[8]
  PIN waddr[9]
    DIRECTION INPUT ;
    USE SIGNAL ;
    ANTENNAGATEAREA 0.631200 ;
    ANTENNADIFFAREA 0.434700 ;
    PORT
      LAYER met2 ;
        RECT 24.470 118.320 24.750 122.320 ;
    END
  END waddr[9]
  PIN wdata[0]
    DIRECTION INPUT ;
    USE SIGNAL ;
    ANTENNAGATEAREA 0.560700 ;
    ANTENNADIFFAREA 0.434700 ;
    PORT
      LAYER met3 ;
        RECT 0.000 12.280 4.000 12.880 ;
    END
  END wdata[0]
  PIN wdata[10]
    DIRECTION INPUT ;
    USE SIGNAL ;
    ANTENNAGATEAREA 0.560700 ;
    ANTENNADIFFAREA 0.434700 ;
    PORT
      LAYER met3 ;
        RECT 0.000 39.480 4.000 40.080 ;
    END
  END wdata[10]
  PIN wdata[11]
    DIRECTION INPUT ;
    USE SIGNAL ;
    ANTENNAGATEAREA 0.560700 ;
    ANTENNADIFFAREA 0.434700 ;
    PORT
      LAYER met3 ;
        RECT 0.000 42.200 4.000 42.800 ;
    END
  END wdata[11]
  PIN wdata[12]
    DIRECTION INPUT ;
    USE SIGNAL ;
    ANTENNAGATEAREA 0.560700 ;
    ANTENNADIFFAREA 0.434700 ;
    PORT
      LAYER met3 ;
        RECT 0.000 44.920 4.000 45.520 ;
    END
  END wdata[12]
  PIN wdata[13]
    DIRECTION INPUT ;
    USE SIGNAL ;
    ANTENNAGATEAREA 0.560700 ;
    ANTENNADIFFAREA 0.434700 ;
    PORT
      LAYER met3 ;
        RECT 0.000 47.640 4.000 48.240 ;
    END
  END wdata[13]
  PIN wdata[14]
    DIRECTION INPUT ;
    USE SIGNAL ;
    ANTENNAGATEAREA 0.560700 ;
    ANTENNADIFFAREA 0.434700 ;
    PORT
      LAYER met3 ;
        RECT 0.000 50.360 4.000 50.960 ;
    END
  END wdata[14]
  PIN wdata[15]
    DIRECTION INPUT ;
    USE SIGNAL ;
    ANTENNAGATEAREA 0.560700 ;
    ANTENNADIFFAREA 0.434700 ;
    PORT
      LAYER met3 ;
        RECT 0.000 53.080 4.000 53.680 ;
    END
  END wdata[15]
  PIN wdata[16]
    DIRECTION INPUT ;
    USE SIGNAL ;
    ANTENNAGATEAREA 0.560700 ;
    ANTENNADIFFAREA 0.434700 ;
    PORT
      LAYER met3 ;
        RECT 0.000 55.800 4.000 56.400 ;
    END
  END wdata[16]
  PIN wdata[17]
    DIRECTION INPUT ;
    USE SIGNAL ;
    ANTENNAGATEAREA 0.560700 ;
    ANTENNADIFFAREA 0.434700 ;
    PORT
      LAYER met3 ;
        RECT 0.000 58.520 4.000 59.120 ;
    END
  END wdata[17]
  PIN wdata[18]
    DIRECTION INPUT ;
    USE SIGNAL ;
    ANTENNAGATEAREA 0.560700 ;
    ANTENNADIFFAREA 0.434700 ;
    PORT
      LAYER met3 ;
        RECT 0.000 61.240 4.000 61.840 ;
    END
  END wdata[18]
  PIN wdata[19]
    DIRECTION INPUT ;
    USE SIGNAL ;
    ANTENNAGATEAREA 0.560700 ;
    ANTENNADIFFAREA 0.434700 ;
    PORT
      LAYER met3 ;
        RECT 0.000 63.960 4.000 64.560 ;
    END
  END wdata[19]
  PIN wdata[1]
    DIRECTION INPUT ;
    USE SIGNAL ;
    ANTENNAGATEAREA 0.560700 ;
    ANTENNADIFFAREA 0.434700 ;
    PORT
      LAYER met3 ;
        RECT 0.000 15.000 4.000 15.600 ;
    END
  END wdata[1]
  PIN wdata[20]
    DIRECTION INPUT ;
    USE SIGNAL ;
    ANTENNAGATEAREA 0.560700 ;
    ANTENNADIFFAREA 0.434700 ;
    PORT
      LAYER met3 ;
        RECT 0.000 66.680 4.000 67.280 ;
    END
  END wdata[20]
  PIN wdata[21]
    DIRECTION INPUT ;
    USE SIGNAL ;
    ANTENNAGATEAREA 0.560700 ;
    ANTENNADIFFAREA 0.434700 ;
    PORT
      LAYER met3 ;
        RECT 0.000 69.400 4.000 70.000 ;
    END
  END wdata[21]
  PIN wdata[22]
    DIRECTION INPUT ;
    USE SIGNAL ;
    ANTENNAGATEAREA 0.560700 ;
    ANTENNADIFFAREA 0.434700 ;
    PORT
      LAYER met3 ;
        RECT 0.000 72.120 4.000 72.720 ;
    END
  END wdata[22]
  PIN wdata[23]
    DIRECTION INPUT ;
    USE SIGNAL ;
    ANTENNAGATEAREA 0.560700 ;
    ANTENNADIFFAREA 0.434700 ;
    PORT
      LAYER met3 ;
        RECT 0.000 74.840 4.000 75.440 ;
    END
  END wdata[23]
  PIN wdata[24]
    DIRECTION INPUT ;
    USE SIGNAL ;
    ANTENNAGATEAREA 0.560700 ;
    ANTENNADIFFAREA 0.434700 ;
    PORT
      LAYER met3 ;
        RECT 0.000 77.560 4.000 78.160 ;
    END
  END wdata[24]
  PIN wdata[25]
    DIRECTION INPUT ;
    USE SIGNAL ;
    ANTENNAGATEAREA 0.560700 ;
    ANTENNADIFFAREA 0.434700 ;
    PORT
      LAYER met3 ;
        RECT 0.000 80.280 4.000 80.880 ;
    END
  END wdata[25]
  PIN wdata[26]
    DIRECTION INPUT ;
    USE SIGNAL ;
    ANTENNAGATEAREA 0.560700 ;
    ANTENNADIFFAREA 0.434700 ;
    PORT
      LAYER met3 ;
        RECT 0.000 83.000 4.000 83.600 ;
    END
  END wdata[26]
  PIN wdata[27]
    DIRECTION INPUT ;
    USE SIGNAL ;
    ANTENNAGATEAREA 0.560700 ;
    ANTENNADIFFAREA 0.434700 ;
    PORT
      LAYER met3 ;
        RECT 0.000 85.720 4.000 86.320 ;
    END
  END wdata[27]
  PIN wdata[28]
    DIRECTION INPUT ;
    USE SIGNAL ;
    ANTENNAGATEAREA 0.560700 ;
    ANTENNADIFFAREA 0.434700 ;
    PORT
      LAYER met3 ;
        RECT 0.000 88.440 4.000 89.040 ;
    END
  END wdata[28]
  PIN wdata[29]
    DIRECTION INPUT ;
    USE SIGNAL ;
    ANTENNAGATEAREA 0.560700 ;
    ANTENNADIFFAREA 0.434700 ;
    PORT
      LAYER met3 ;
        RECT 0.000 91.160 4.000 91.760 ;
    END
  END wdata[29]
  PIN wdata[2]
    DIRECTION INPUT ;
    USE SIGNAL ;
    ANTENNAGATEAREA 0.560700 ;
    ANTENNADIFFAREA 0.434700 ;
    PORT
      LAYER met3 ;
        RECT 0.000 17.720 4.000 18.320 ;
    END
  END wdata[2]
  PIN wdata[30]
    DIRECTION INPUT ;
    USE SIGNAL ;
    ANTENNAGATEAREA 0.560700 ;
    ANTENNADIFFAREA 0.434700 ;
    PORT
      LAYER met3 ;
        RECT 0.000 93.880 4.000 94.480 ;
    END
  END wdata[30]
  PIN wdata[31]
    DIRECTION INPUT ;
    USE SIGNAL ;
    ANTENNAGATEAREA 0.995400 ;
    ANTENNADIFFAREA 0.869400 ;
    PORT
      LAYER met3 ;
        RECT 0.000 96.600 4.000 97.200 ;
    END
  END wdata[31]
  PIN wdata[3]
    DIRECTION INPUT ;
    USE SIGNAL ;
    ANTENNAGATEAREA 0.560700 ;
    ANTENNADIFFAREA 0.434700 ;
    PORT
      LAYER met3 ;
        RECT 0.000 20.440 4.000 21.040 ;
    END
  END wdata[3]
  PIN wdata[4]
    DIRECTION INPUT ;
    USE SIGNAL ;
    ANTENNAGATEAREA 0.560700 ;
    ANTENNADIFFAREA 0.434700 ;
    PORT
      LAYER met3 ;
        RECT 0.000 23.160 4.000 23.760 ;
    END
  END wdata[4]
  PIN wdata[5]
    DIRECTION INPUT ;
    USE SIGNAL ;
    ANTENNAGATEAREA 0.560700 ;
    ANTENNADIFFAREA 0.434700 ;
    PORT
      LAYER met3 ;
        RECT 0.000 25.880 4.000 26.480 ;
    END
  END wdata[5]
  PIN wdata[6]
    DIRECTION INPUT ;
    USE SIGNAL ;
    ANTENNAGATEAREA 0.560700 ;
    ANTENNADIFFAREA 0.434700 ;
    PORT
      LAYER met3 ;
        RECT 0.000 28.600 4.000 29.200 ;
    END
  END wdata[6]
  PIN wdata[7]
    DIRECTION INPUT ;
    USE SIGNAL ;
    ANTENNAGATEAREA 0.560700 ;
    ANTENNADIFFAREA 0.434700 ;
    PORT
      LAYER met3 ;
        RECT 0.000 31.320 4.000 31.920 ;
    END
  END wdata[7]
  PIN wdata[8]
    DIRECTION INPUT ;
    USE SIGNAL ;
    ANTENNAGATEAREA 0.560700 ;
    ANTENNADIFFAREA 0.434700 ;
    PORT
      LAYER met3 ;
        RECT 0.000 34.040 4.000 34.640 ;
    END
  END wdata[8]
  PIN wdata[9]
    DIRECTION INPUT ;
    USE SIGNAL ;
    ANTENNAGATEAREA 0.560700 ;
    ANTENNADIFFAREA 0.434700 ;
    PORT
      LAYER met3 ;
        RECT 0.000 36.760 4.000 37.360 ;
    END
  END wdata[9]
  PIN wen
    DIRECTION INPUT ;
    USE SIGNAL ;
    ANTENNAGATEAREA 0.631200 ;
    ANTENNADIFFAREA 0.434700 ;
    PORT
      LAYER met3 ;
        RECT 0.000 99.320 4.000 99.920 ;
    END
  END wen
  PIN wready
    DIRECTION OUTPUT ;
    USE SIGNAL ;
    ANTENNAGATEAREA 0.434700 ;
    ANTENNADIFFAREA 0.434700 ;
    PORT
      LAYER met3 ;
        RECT 0.000 112.920 4.000 113.520 ;
    END
  END wready
  PIN wstrb[0]
    DIRECTION INPUT ;
    USE SIGNAL ;
    ANTENNAGATEAREA 0.995400 ;
    ANTENNADIFFAREA 0.869400 ;
    PORT
      LAYER met3 ;
        RECT 0.000 102.040 4.000 102.640 ;
    END
  END wstrb[0]
  PIN wstrb[1]
    DIRECTION INPUT ;
    USE SIGNAL ;
    ANTENNAGATEAREA 0.995400 ;
    ANTENNADIFFAREA 0.869400 ;
    PORT
      LAYER met3 ;
        RECT 0.000 104.760 4.000 105.360 ;
    END
  END wstrb[1]
  PIN wstrb[2]
    DIRECTION INPUT ;
    USE SIGNAL ;
    ANTENNAGATEAREA 0.995400 ;
    ANTENNADIFFAREA 0.869400 ;
    PORT
      LAYER met3 ;
        RECT 0.000 107.480 4.000 108.080 ;
    END
  END wstrb[2]
  PIN wstrb[3]
    DIRECTION INPUT ;
    USE SIGNAL ;
    ANTENNAGATEAREA 0.995400 ;
    ANTENNADIFFAREA 0.869400 ;
    PORT
      LAYER met3 ;
        RECT 0.000 110.200 4.000 110.800 ;
    END
  END wstrb[3]
  OBS
      LAYER nwell ;
        RECT 5.330 10.795 105.990 108.885 ;
      LAYER li1 ;
        RECT 5.520 10.795 105.800 108.885 ;
      LAYER met1 ;
        RECT 2.370 0.380 108.950 111.140 ;
      LAYER met2 ;
        RECT 2.400 118.040 11.770 118.320 ;
        RECT 12.610 118.040 13.150 118.320 ;
        RECT 13.990 118.040 14.530 118.320 ;
        RECT 15.370 118.040 15.910 118.320 ;
        RECT 16.750 118.040 17.290 118.320 ;
        RECT 18.130 118.040 18.670 118.320 ;
        RECT 19.510 118.040 20.050 118.320 ;
        RECT 20.890 118.040 21.430 118.320 ;
        RECT 22.270 118.040 22.810 118.320 ;
        RECT 23.650 118.040 24.190 118.320 ;
        RECT 25.030 118.040 25.570 118.320 ;
        RECT 26.410 118.040 26.950 118.320 ;
        RECT 27.790 118.040 28.330 118.320 ;
        RECT 29.170 118.040 29.710 118.320 ;
        RECT 30.550 118.040 31.090 118.320 ;
        RECT 31.930 118.040 32.470 118.320 ;
        RECT 33.310 118.040 33.850 118.320 ;
        RECT 34.690 118.040 35.230 118.320 ;
        RECT 36.070 118.040 36.610 118.320 ;
        RECT 37.450 118.040 37.990 118.320 ;
        RECT 38.830 118.040 39.370 118.320 ;
        RECT 40.210 118.040 40.750 118.320 ;
        RECT 41.590 118.040 42.130 118.320 ;
        RECT 42.970 118.040 43.510 118.320 ;
        RECT 44.350 118.040 44.890 118.320 ;
        RECT 45.730 118.040 46.270 118.320 ;
        RECT 47.110 118.040 47.650 118.320 ;
        RECT 48.490 118.040 49.030 118.320 ;
        RECT 49.870 118.040 50.410 118.320 ;
        RECT 51.250 118.040 51.790 118.320 ;
        RECT 52.630 118.040 53.170 118.320 ;
        RECT 54.010 118.040 54.550 118.320 ;
        RECT 55.390 118.040 55.930 118.320 ;
        RECT 56.770 118.040 57.310 118.320 ;
        RECT 58.150 118.040 58.690 118.320 ;
        RECT 59.530 118.040 60.070 118.320 ;
        RECT 60.910 118.040 61.450 118.320 ;
        RECT 62.290 118.040 62.830 118.320 ;
        RECT 63.670 118.040 64.210 118.320 ;
        RECT 65.050 118.040 65.590 118.320 ;
        RECT 66.430 118.040 66.970 118.320 ;
        RECT 67.810 118.040 68.350 118.320 ;
        RECT 69.190 118.040 69.730 118.320 ;
        RECT 70.570 118.040 71.110 118.320 ;
        RECT 71.950 118.040 72.490 118.320 ;
        RECT 73.330 118.040 73.870 118.320 ;
        RECT 74.710 118.040 75.250 118.320 ;
        RECT 76.090 118.040 76.630 118.320 ;
        RECT 77.470 118.040 78.010 118.320 ;
        RECT 78.850 118.040 79.390 118.320 ;
        RECT 80.230 118.040 80.770 118.320 ;
        RECT 81.610 118.040 82.150 118.320 ;
        RECT 82.990 118.040 83.530 118.320 ;
        RECT 84.370 118.040 84.910 118.320 ;
        RECT 85.750 118.040 86.290 118.320 ;
        RECT 87.130 118.040 87.670 118.320 ;
        RECT 88.510 118.040 89.050 118.320 ;
        RECT 89.890 118.040 90.430 118.320 ;
        RECT 91.270 118.040 91.810 118.320 ;
        RECT 92.650 118.040 93.190 118.320 ;
        RECT 94.030 118.040 94.570 118.320 ;
        RECT 95.410 118.040 95.950 118.320 ;
        RECT 96.790 118.040 97.330 118.320 ;
        RECT 98.170 118.040 98.710 118.320 ;
        RECT 99.550 118.040 108.920 118.320 ;
        RECT 2.400 4.280 108.920 118.040 ;
        RECT 2.950 0.350 5.330 4.280 ;
        RECT 6.170 0.350 8.550 4.280 ;
        RECT 9.390 0.350 11.770 4.280 ;
        RECT 12.610 0.350 14.990 4.280 ;
        RECT 15.830 0.350 18.210 4.280 ;
        RECT 19.050 0.350 21.430 4.280 ;
        RECT 22.270 0.350 24.650 4.280 ;
        RECT 25.490 0.350 27.870 4.280 ;
        RECT 28.710 0.350 31.090 4.280 ;
        RECT 31.930 0.350 34.310 4.280 ;
        RECT 35.150 0.350 37.530 4.280 ;
        RECT 38.370 0.350 40.750 4.280 ;
        RECT 41.590 0.350 43.970 4.280 ;
        RECT 44.810 0.350 47.190 4.280 ;
        RECT 48.030 0.350 50.410 4.280 ;
        RECT 51.250 0.350 53.630 4.280 ;
        RECT 54.470 0.350 56.850 4.280 ;
        RECT 57.690 0.350 60.070 4.280 ;
        RECT 60.910 0.350 63.290 4.280 ;
        RECT 64.130 0.350 66.510 4.280 ;
        RECT 67.350 0.350 69.730 4.280 ;
        RECT 70.570 0.350 72.950 4.280 ;
        RECT 73.790 0.350 76.170 4.280 ;
        RECT 77.010 0.350 79.390 4.280 ;
        RECT 80.230 0.350 82.610 4.280 ;
        RECT 83.450 0.350 85.830 4.280 ;
        RECT 86.670 0.350 89.050 4.280 ;
        RECT 89.890 0.350 92.270 4.280 ;
        RECT 93.110 0.350 95.490 4.280 ;
        RECT 96.330 0.350 98.710 4.280 ;
        RECT 99.550 0.350 101.930 4.280 ;
        RECT 102.770 0.350 105.150 4.280 ;
        RECT 105.990 0.350 108.370 4.280 ;
      LAYER met3 ;
        RECT 4.400 112.520 107.600 113.380 ;
        RECT 4.000 111.200 107.600 112.520 ;
        RECT 4.400 109.800 107.600 111.200 ;
        RECT 4.000 108.480 107.600 109.800 ;
        RECT 4.400 107.080 107.600 108.480 ;
        RECT 4.000 105.760 107.600 107.080 ;
        RECT 4.400 104.360 107.600 105.760 ;
        RECT 4.000 103.040 107.600 104.360 ;
        RECT 4.400 101.640 107.200 103.040 ;
        RECT 4.000 100.320 107.600 101.640 ;
        RECT 4.400 98.920 107.200 100.320 ;
        RECT 4.000 97.600 107.600 98.920 ;
        RECT 4.400 96.200 107.200 97.600 ;
        RECT 4.000 94.880 107.600 96.200 ;
        RECT 4.400 93.480 107.200 94.880 ;
        RECT 4.000 92.160 107.600 93.480 ;
        RECT 4.400 90.760 107.200 92.160 ;
        RECT 4.000 89.440 107.600 90.760 ;
        RECT 4.400 88.040 107.200 89.440 ;
        RECT 4.000 86.720 107.600 88.040 ;
        RECT 4.400 85.320 107.200 86.720 ;
        RECT 4.000 84.000 107.600 85.320 ;
        RECT 4.400 82.600 107.200 84.000 ;
        RECT 4.000 81.280 107.600 82.600 ;
        RECT 4.400 79.880 107.200 81.280 ;
        RECT 4.000 78.560 107.600 79.880 ;
        RECT 4.400 77.160 107.200 78.560 ;
        RECT 4.000 75.840 107.600 77.160 ;
        RECT 4.400 74.440 107.200 75.840 ;
        RECT 4.000 73.120 107.600 74.440 ;
        RECT 4.400 71.720 107.200 73.120 ;
        RECT 4.000 70.400 107.600 71.720 ;
        RECT 4.400 69.000 107.200 70.400 ;
        RECT 4.000 67.680 107.600 69.000 ;
        RECT 4.400 66.280 107.200 67.680 ;
        RECT 4.000 64.960 107.600 66.280 ;
        RECT 4.400 63.560 107.200 64.960 ;
        RECT 4.000 62.240 107.600 63.560 ;
        RECT 4.400 60.840 107.200 62.240 ;
        RECT 4.000 59.520 107.600 60.840 ;
        RECT 4.400 58.120 107.200 59.520 ;
        RECT 4.000 56.800 107.600 58.120 ;
        RECT 4.400 55.400 107.200 56.800 ;
        RECT 4.000 54.080 107.600 55.400 ;
        RECT 4.400 52.680 107.200 54.080 ;
        RECT 4.000 51.360 107.600 52.680 ;
        RECT 4.400 49.960 107.200 51.360 ;
        RECT 4.000 48.640 107.600 49.960 ;
        RECT 4.400 47.240 107.200 48.640 ;
        RECT 4.000 45.920 107.600 47.240 ;
        RECT 4.400 44.520 107.200 45.920 ;
        RECT 4.000 43.200 107.600 44.520 ;
        RECT 4.400 41.800 107.200 43.200 ;
        RECT 4.000 40.480 107.600 41.800 ;
        RECT 4.400 39.080 107.200 40.480 ;
        RECT 4.000 37.760 107.600 39.080 ;
        RECT 4.400 36.360 107.200 37.760 ;
        RECT 4.000 35.040 107.600 36.360 ;
        RECT 4.400 33.640 107.200 35.040 ;
        RECT 4.000 32.320 107.600 33.640 ;
        RECT 4.400 30.920 107.200 32.320 ;
        RECT 4.000 29.600 107.600 30.920 ;
        RECT 4.400 28.200 107.200 29.600 ;
        RECT 4.000 26.880 107.600 28.200 ;
        RECT 4.400 25.480 107.200 26.880 ;
        RECT 4.000 24.160 107.600 25.480 ;
        RECT 4.400 22.760 107.200 24.160 ;
        RECT 4.000 21.440 107.600 22.760 ;
        RECT 4.400 20.040 107.200 21.440 ;
        RECT 4.000 18.720 107.600 20.040 ;
        RECT 4.400 17.320 107.200 18.720 ;
        RECT 4.000 16.000 107.600 17.320 ;
        RECT 4.400 14.600 107.600 16.000 ;
        RECT 4.000 13.280 107.600 14.600 ;
        RECT 4.400 11.880 107.600 13.280 ;
        RECT 4.000 10.560 107.600 11.880 ;
        RECT 4.400 9.160 107.600 10.560 ;
        RECT 4.000 7.840 107.600 9.160 ;
        RECT 4.400 6.440 107.600 7.840 ;
        RECT 4.000 6.295 107.600 6.440 ;
      LAYER met4 ;
        RECT 6.735 109.440 85.265 113.385 ;
        RECT 6.735 10.240 20.640 109.440 ;
        RECT 23.040 10.240 23.940 109.440 ;
        RECT 26.340 10.240 85.265 109.440 ;
        RECT 6.735 6.295 85.265 10.240 ;
  END
END gpio_ip
END LIBRARY

